One B-rep face of a CAD part: STEP entity #277.
In plain terms, the cylindrical face has radius 16 mm (diameter 32 mm), a partial arc.
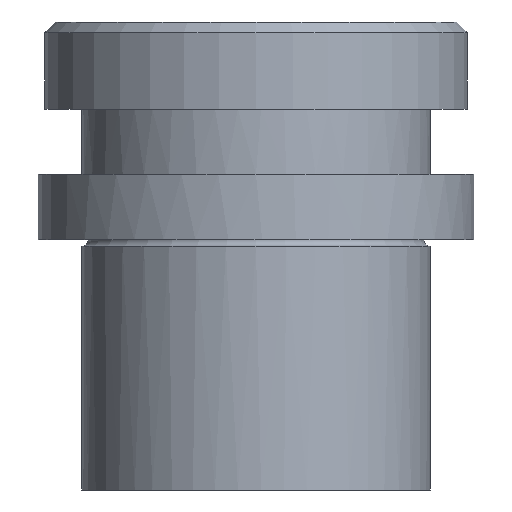
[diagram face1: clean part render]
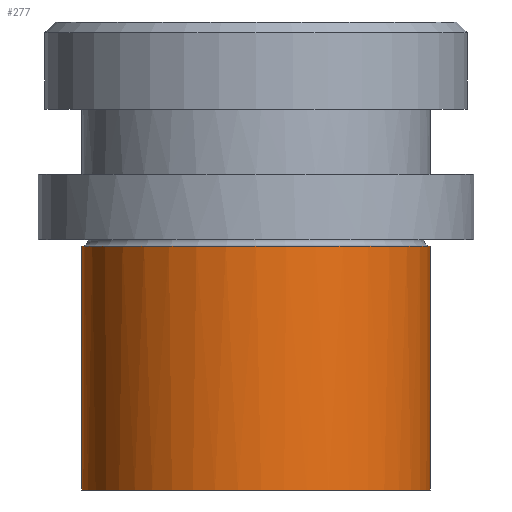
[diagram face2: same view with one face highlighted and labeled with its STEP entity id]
Its self-contained STEP definition (entity closure, numbers rounded to 3 decimals):
#109=CARTESIAN_POINT('Control Point',(-16.,0.,-23.)) ;
#110=CARTESIAN_POINT('Control Point',(-16.,-1.568,-23.)) ;
#111=CARTESIAN_POINT('Control Point',(-15.808,-3.135,-23.)) ;
#112=CARTESIAN_POINT('Control Point',(-15.424,-4.672,-23.)) ;
#113=CARTESIAN_POINT('Control Point',(-14.288,-7.619,-23.)) ;
#114=CARTESIAN_POINT('Control Point',(-12.473,-10.205,-23.)) ;
#115=CARTESIAN_POINT('Control Point',(-11.412,-11.38,-23.)) ;
#116=CARTESIAN_POINT('Control Point',(-9.022,-13.446,-23.)) ;
#117=CARTESIAN_POINT('Control Point',(-6.205,-14.874,-23.)) ;
#118=CARTESIAN_POINT('Control Point',(-4.715,-15.411,-23.)) ;
#119=CARTESIAN_POINT('Control Point',(-1.634,-16.109,-23.)) ;
#120=CARTESIAN_POINT('Control Point',(1.524,-16.044,-23.)) ;
#121=CARTESIAN_POINT('Control Point',(3.091,-15.817,-23.)) ;
#122=CARTESIAN_POINT('Control Point',(6.138,-14.984,-23.)) ;
#123=CARTESIAN_POINT('Control Point',(8.894,-13.44,-23.)) ;
#124=CARTESIAN_POINT('Control Point',(10.17,-12.502,-23.)) ;
#125=CARTESIAN_POINT('Control Point',(12.466,-10.333,-23.)) ;
#126=CARTESIAN_POINT('Control Point',(14.171,-7.674,-23.)) ;
#127=CARTESIAN_POINT('Control Point',(14.856,-6.246,-23.)) ;
#128=CARTESIAN_POINT('Control Point',(15.567,-4.131,-23.)) ;
#129=CARTESIAN_POINT('Control Point',(15.902,-1.939,-23.)) ;
#130=CARTESIAN_POINT('Control Point',(15.967,-1.294,-23.)) ;
#131=CARTESIAN_POINT('Control Point',(16.,-0.647,-23.)) ;
#132=CARTESIAN_POINT('Control Point',(16.,0.,-23.)) ;
#133=CARTESIAN_POINT('Vertex',(-16.,0.,-23.)) ;
#135=CARTESIAN_POINT('Vertex',(16.,0.,-23.)) ;
#247=CARTESIAN_POINT('Axis2P3D Location',(0.,0.,20.)) ;
#252=CARTESIAN_POINT('Line Origine',(16.,0.,20.)) ;
#256=CARTESIAN_POINT('Vertex',(16.,0.,-0.6)) ;
#259=CARTESIAN_POINT('Axis2P3D Location',(0.,0.,-0.6)) ;
#263=CARTESIAN_POINT('Vertex',(-16.,0.,-0.6)) ;
#266=CARTESIAN_POINT('Line Origine',(-16.,0.,20.)) ;
#248=DIRECTION('Axis2P3D Direction',(0.,0.,-1.)) ;
#249=DIRECTION('Axis2P3D XDirection',(1.,0.,0.)) ;
#253=DIRECTION('Vector Direction',(0.,0.,-1.)) ;
#260=DIRECTION('Axis2P3D Direction',(0.,0.,-1.)) ;
#267=DIRECTION('Vector Direction',(0.,0.,-1.)) ;
#250=AXIS2_PLACEMENT_3D('Cylinder Axis2P3D',#247,#248,#249) ;
#261=AXIS2_PLACEMENT_3D('Circle Axis2P3D',#259,#260,$) ;
#272=ORIENTED_EDGE('',*,*,#258,.T.) ;
#273=ORIENTED_EDGE('',*,*,#265,.F.) ;
#274=ORIENTED_EDGE('',*,*,#270,.T.) ;
#275=ORIENTED_EDGE('',*,*,#137,.T.) ;
#254=VECTOR('Line Direction',#253,1.) ;
#268=VECTOR('Line Direction',#267,1.) ;
#277=ADVANCED_FACE('735-19',(#276),#251,.T.) ;
#108=B_SPLINE_CURVE_WITH_KNOTS('',5,(#109,#110,#111,#112,#113,#114,#115,#116,#117,#118,#119,#120,#121,#122,#123,#124,#125,#126,#127,#128,#129,#130,#131,#132),.UNSPECIFIED.,.F.,.U.,(6,3,3,3,3,3,3,6),(0.,11.085,22.17,33.255,44.34,55.425,66.51,71.085),.UNSPECIFIED.) ;
#262=CIRCLE('generated circle',#261,16.) ;
#251=CYLINDRICAL_SURFACE('generated cylinder',#250,16.) ;
#137=EDGE_CURVE('',#134,#136,#108,.T.) ;
#258=EDGE_CURVE('',#136,#257,#255,.F.) ;
#265=EDGE_CURVE('',#264,#257,#262,.F.) ;
#270=EDGE_CURVE('',#264,#134,#269,.T.) ;
#271=EDGE_LOOP('',(#272,#273,#274,#275)) ;
#276=FACE_OUTER_BOUND('',#271,.T.) ;
#255=LINE('Line',#252,#254) ;
#269=LINE('Line',#266,#268) ;
#134=VERTEX_POINT('',#133) ;
#136=VERTEX_POINT('',#135) ;
#257=VERTEX_POINT('',#256) ;
#264=VERTEX_POINT('',#263) ;
